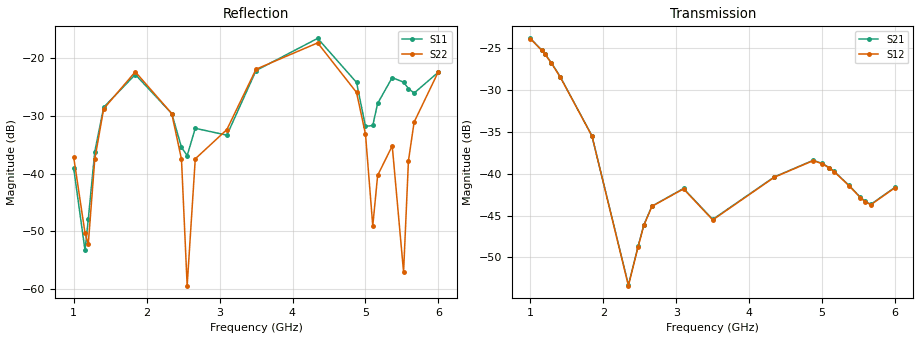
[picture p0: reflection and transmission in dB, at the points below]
!Agilent Technologies,E8364B,MY43040528,A.07.50.67
!Agilent E8364B: A.07.50.67
!Date: Sunday, March 01, 2026 16:15:32
!Correction: S11(Full 2 Port(1,2))
!S21(Full 2 Port(1,2))
!S12(Full 2 Port(1,2))
!S22(Full 2 Port(1,2))
!S2P File: Measurements: S11, S21, S12, S22:
# Hz S  dB  R 50
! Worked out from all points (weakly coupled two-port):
!   451 points, 1 GHz to 6 GHz, reference 50 ohm
!   highest |S21| = -23.82 dB at 1 GHz (marker M1); lowest = -53.3 dB at 2.344 GHz (marker M2)
!   lowest |S11| = -53.3 dB at 1.156 GHz (marker M3), VSWR 1.00, Z = 49.9 + j0.173 ohm
!   |S11| at or under -10 dB: start of sweep to end of sweep
!   |S22| runs from -61.4 to -17.2 dB; largest |S21 - S12| = 0.00029
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1e9  -39.04 33.6  -23.82 153.2  -23.86 153.2  -37.13 -24.8
1.155556e9  -53.28 126.9  -25.22 64.3  -25.25 64.3  -50.29 12.7
1.2e9  -47.91 178.3  -25.69 38.9  -25.72 38.9  -52.21 99.0
1.288889e9  -36.21 -164.1  -26.74 -11.4  -26.78 -11.4  -37.52 133.0
1.411111e9  -28.51 176.1  -28.43 -79.4  -28.47 -79.4  -28.76 107.7
1.844444e9  -22.83 88.2  -35.47 48.2  -35.49 48.3  -22.36 -0.7
2.344444e9  -29.58 26.2  -53.30 -149.2  -53.38 -149.2  -29.59 -104.2
2.477778e9  -35.43 29.2  -48.66 -166.9  -48.71 -166.8  -37.51 -137.0
2.555556e9  -36.88 64.0  -46.13 159.9  -46.17 159.9  -59.39 175.5
2.666667e9  -32.14 82.3  -43.87 105.1  -43.90 105.1  -37.43 -2.9
3.1e9  -33.33 70.1  -41.76 -123.8  -41.81 -123.7  -32.36 -29.0
3.5e9  -22.14 56.4  -45.46 37.8  -45.52 37.8  -21.91 -103.2
4.344444e9  -16.57 -40.1  -40.38 23.9  -40.42 23.9  -17.35 102.6
4.877778e9  -24.21 -125.2  -38.39 82.9  -38.43 82.9  -25.94 -29.5
5e9  -31.81 -119.6  -38.77 10.6  -38.80 10.7  -33.15 -68.1
5.1e9  -31.65 -62.3  -39.29 -49.2  -39.33 -49.1  -49.03 -159.0
5.166667e9  -27.83 -54.2  -39.73 -89.5  -39.77 -89.4  -40.29 90.6
5.366667e9  -23.36 -79.0  -41.38 145.6  -41.42 145.7  -35.19 18.7
5.522222e9  -24.16 -97.3  -42.79 41.5  -42.84 41.5  -57.04 54.3
5.588889e9  -25.26 -99.9  -43.30 -5.4  -43.33 -5.5  -37.78 114.9
5.666667e9  -26.04 -96.3  -43.66 -61.8  -43.71 -61.8  -31.07 95.4
6e9  -22.41 -90.9  -41.61 61.4  -41.66 61.4  -22.32 2.8
